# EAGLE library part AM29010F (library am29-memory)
1-Megabit FLASH MEMORY (128 x 8 bit/64 K x 16 bit) 5 V-only

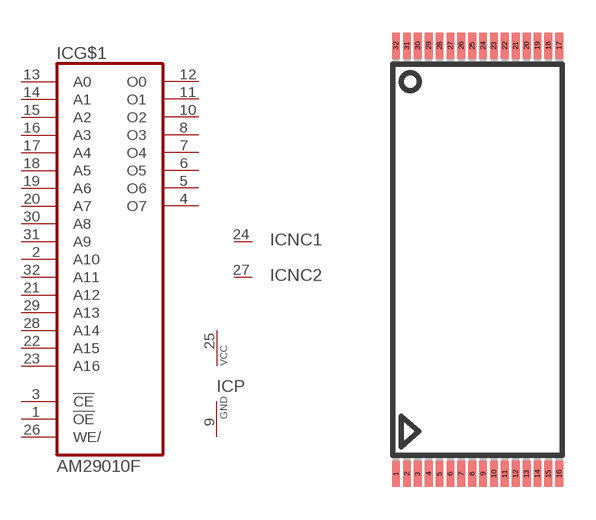
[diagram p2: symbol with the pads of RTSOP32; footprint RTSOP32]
Designator prefix IC; gates G$1=AM29F010 P=VCC-GND NC1=NC NC2=NC

## AM29010F  [RTSOP32]
1  G$1:!OE  in
2  G$1:A10  in
3  G$1:!CE  in
4  G$1:O7  hiz
5  G$1:O6  hiz
6  G$1:O5  hiz
7  G$1:O4  hiz
8  G$1:O3  hiz
9  P:GND  pwr
10  G$1:O2  hiz
11  G$1:O1  hiz
12  G$1:O0  hiz
13  G$1:A0  in
14  G$1:A1  in
15  G$1:A2  in
16  G$1:A3  in
17  G$1:A4  in
18  G$1:A5  in
19  G$1:A6  in
20  G$1:A7  in
21  G$1:A12  in
22  G$1:A15  in
23  G$1:A16  in
24  NC1:NC  nc
25  P:VCC  pwr
26  G$1:WE/  in
27  NC2:NC  nc
28  G$1:A14  in
29  G$1:A13  in
30  G$1:A8  in
31  G$1:A9  in
32  G$1:A11  in

## Footprint RTSOP32 (pad centres in mm)
Reverse TSOP32
smd 0.36 x 1.2: 1 -3.75,-9.85; 2 -3.25,-9.85; 3 -2.75,-9.85; 4 -2.25,-9.85; 5 -1.75,-9.85; 6 -1.25,-9.85; 7 -0.75,-9.85; 8 -0.25,-9.85; 9 0.25,-9.85; 10 0.75,-9.85; 11 1.25,-9.85; 12 1.75,-9.85; 13 2.25,-9.85; 14 2.75,-9.85; 15 3.25,-9.85; 16 3.75,-9.85; 17 3.75,9.85; 18 3.25,9.85; 19 2.75,9.85; 20 2.25,9.85; 21 1.75,9.85; 22 1.25,9.85; 23 0.75,9.85; 24 0.25,9.85; 25 -0.25,9.85; 26 -0.75,9.85; 27 -1.25,9.85; 28 -1.75,9.85; 29 -2.25,9.85; 30 -2.75,9.85; 31 -3.25,9.85; 32 -3.75,9.85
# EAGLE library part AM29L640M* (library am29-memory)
64 Megabit (4 M x 16-Bit/8 M x 8-Bit) MirrorBit 3.0 Volt-only Uniform Sector Flash Memory with VersatileI/O Control Source: www.amd.com .. 26191.pdf

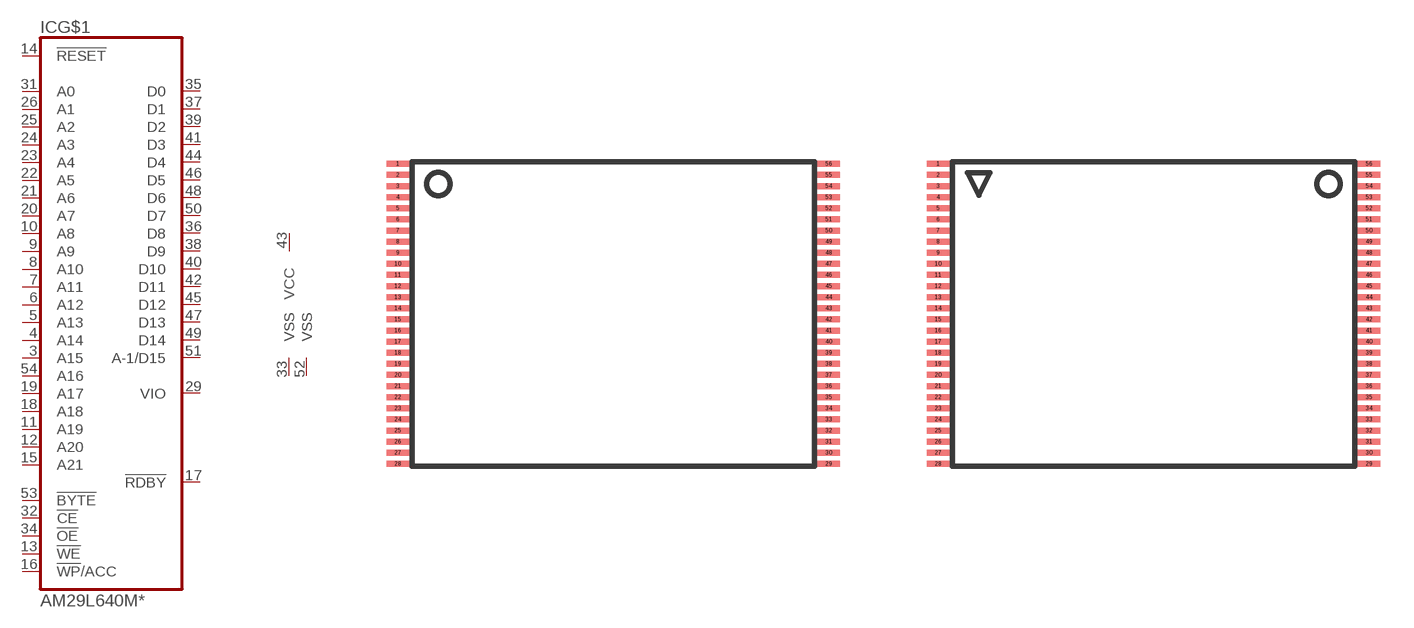
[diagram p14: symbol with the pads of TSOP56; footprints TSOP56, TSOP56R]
Designator prefix IC; gates G$1=29LV640 G$2=VCCVSS2

## AM29L640MH101RE, AM29L640MH112E, AM29L640MH112RE, AM29L640MH120E, AM29L640MH120RE, AM29L640MH90RE, AM29L640ML101RE, AM29L640ML112E, AM29L640ML112RE, AM29L640ML120E, AM29L640ML120RE, AM29L640ML90RE  [TSOP56]
3  G$1:A15  in
4  G$1:A14  in
5  G$1:A13  in
6  G$1:A12  in
7  G$1:A11  in
8  G$1:A10  in
9  G$1:A9  in
10  G$1:A8  in
11  G$1:A19  in
12  G$1:A20  in
13  G$1:!WE  in
14  G$1:!RESET  in
15  G$1:A21  in
16  G$1:!WP!/ACC  in
17  G$1:!RDBY  out
18  G$1:A18  in
19  G$1:A17  in
20  G$1:A7  in
21  G$1:A6  in
22  G$1:A5  in
23  G$1:A4  in
24  G$1:A3  in
25  G$1:A2  in
26  G$1:A1  in
29  G$1:VIO  pwr
31  G$1:A0  in
32  G$1:!CE  in
33  G$2:VSS  pwr
34  G$1:!OE  in
35  G$1:D0  hiz
36  G$1:D8  hiz
37  G$1:D1  hiz
38  G$1:D9  hiz
39  G$1:D2  hiz
40  G$1:D10  hiz
41  G$1:D3  hiz
42  G$1:D11  hiz
43  G$2:VCC  pwr
44  G$1:D4  hiz
45  G$1:D12  hiz
46  G$1:D5  hiz
47  G$1:D13  hiz
48  G$1:D6  hiz
49  G$1:D14  hiz
50  G$1:D7  hiz
51  G$1:A-1/D15  hiz
52  G$2:VSS  pwr
53  G$1:!BYTE  in
54  G$1:A16  in

## AM29L640MH101RF, AM29L640MH112F, AM29L640MH112RF, AM29L640MH120F, AM29L640MH120RF, AM29L640MH90RF, AM29L640ML101RF, AM29L640ML112F, AM29L640ML112RF, AM29L640ML120F, AM29L640ML120RF, AM29L640ML90RF  [TSOP56R]
3  G$1:A16  in
4  G$1:!BYTE  in
5  G$2:VSS  pwr
6  G$1:A-1/D15  hiz
7  G$1:D7  hiz
8  G$1:D14  hiz
9  G$1:D6  hiz
10  G$1:D13  hiz
11  G$1:D5  hiz
12  G$1:D12  hiz
13  G$1:D4  hiz
14  G$2:VCC  pwr
15  G$1:D11  hiz
16  G$1:D3  hiz
17  G$1:D10  hiz
18  G$1:D2  hiz
19  G$1:D9  hiz
20  G$1:D1  hiz
21  G$1:D8  hiz
22  G$1:D0  hiz
23  G$1:!OE  in
24  G$2:VSS  pwr
25  G$1:!CE  in
26  G$1:A0  in
28  G$1:VIO  pwr
31  G$1:A1  in
32  G$1:A2  in
33  G$1:A3  in
34  G$1:A4  in
35  G$1:A5  in
36  G$1:A6  in
37  G$1:A7  in
38  G$1:A17  in
39  G$1:A18  in
40  G$1:!RDBY  out
41  G$1:!WP!/ACC  in
42  G$1:A21  in
43  G$1:!RESET  in
44  G$1:!WE  in
45  G$1:A20  in
46  G$1:A19  in
47  G$1:A8  in
48  G$1:A9  in
49  G$1:A10  in
50  G$1:A11  in
51  G$1:A12  in
52  G$1:A13  in
53  G$1:A14  in
54  G$1:A15  in

## Footprint TSOP56 (pad centres in mm)
TS056/TSR056 56-Pin Thin Small Outline Package (TSOP) Standard Pinout Source: www.amd.com .. 26191.pdf
smd 1 x 0.27: 1 -9.7,6.75; 2 -9.7,6.25; 3 -9.7,5.75; 4 -9.7,5.25; 5 -9.7,4.75; 6 -9.7,4.25; 7 -9.7,3.75; 8 -9.7,3.25; 9 -9.7,2.75; 10 -9.7,2.25; 11 -9.7,1.75; 12 -9.7,1.25; 13 -9.7,0.75; 14 -9.7,0.25; 15 -9.7,-0.25; 16 -9.7,-0.75; 17 -9.7,-1.25; 18 -9.7,-1.75; 19 -9.7,-2.25; 20 -9.7,-2.75; 21 -9.7,-3.25; 22 -9.7,-3.75; 23 -9.7,-4.25; 24 -9.7,-4.75; 25 -9.7,-5.25; 26 -9.7,-5.75; 27 -9.7,-6.25; 28 -9.7,-6.75; 29 9.7,-6.75; 30 9.7,-6.25; 31 9.7,-5.75; 32 9.7,-5.25; 33 9.7,-4.75; 34 9.7,-4.25; 35 9.7,-3.75; 36 9.7,-3.25; 37 9.7,-2.75; 38 9.7,-2.25; 39 9.7,-1.75; 40 9.7,-1.25; 41 9.7,-0.75; 42 9.7,-0.25; 43 9.7,0.25; 44 9.7,0.75; 45 9.7,1.25; 46 9.7,1.75; 47 9.7,2.25; 48 9.7,2.75; 49 9.7,3.25; 50 9.7,3.75; 51 9.7,4.25; 52 9.7,4.75; 53 9.7,5.25; 54 9.7,5.75; 55 9.7,6.25; 56 9.7,6.75

## Footprint TSOP56R (pad centres in mm)
TS056/TSR056 56-Pin Thin Small Outline Package (TSOP) Reverse Pinout Source: www.amd.com .. 26191.pdf
smd 1 x 0.27: 1 -9.7,6.75; 2 -9.7,6.25; 3 -9.7,5.75; 4 -9.7,5.25; 5 -9.7,4.75; 6 -9.7,4.25; 7 -9.7,3.75; 8 -9.7,3.25; 9 -9.7,2.75; 10 -9.7,2.25; 11 -9.7,1.75; 12 -9.7,1.25; 13 -9.7,0.75; 14 -9.7,0.25; 15 -9.7,-0.25; 16 -9.7,-0.75; 17 -9.7,-1.25; 18 -9.7,-1.75; 19 -9.7,-2.25; 20 -9.7,-2.75; 21 -9.7,-3.25; 22 -9.7,-3.75; 23 -9.7,-4.25; 24 -9.7,-4.75; 25 -9.7,-5.25; 26 -9.7,-5.75; 27 -9.7,-6.25; 28 -9.7,-6.75; 29 9.7,-6.75; 30 9.7,-6.25; 31 9.7,-5.75; 32 9.7,-5.25; 33 9.7,-4.75; 34 9.7,-4.25; 35 9.7,-3.75; 36 9.7,-3.25; 37 9.7,-2.75; 38 9.7,-2.25; 39 9.7,-1.75; 40 9.7,-1.25; 41 9.7,-0.75; 42 9.7,-0.25; 43 9.7,0.25; 44 9.7,0.75; 45 9.7,1.25; 46 9.7,1.75; 47 9.7,2.25; 48 9.7,2.75; 49 9.7,3.25; 50 9.7,3.75; 51 9.7,4.25; 52 9.7,4.75; 53 9.7,5.25; 54 9.7,5.75; 55 9.7,6.25; 56 9.7,6.75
